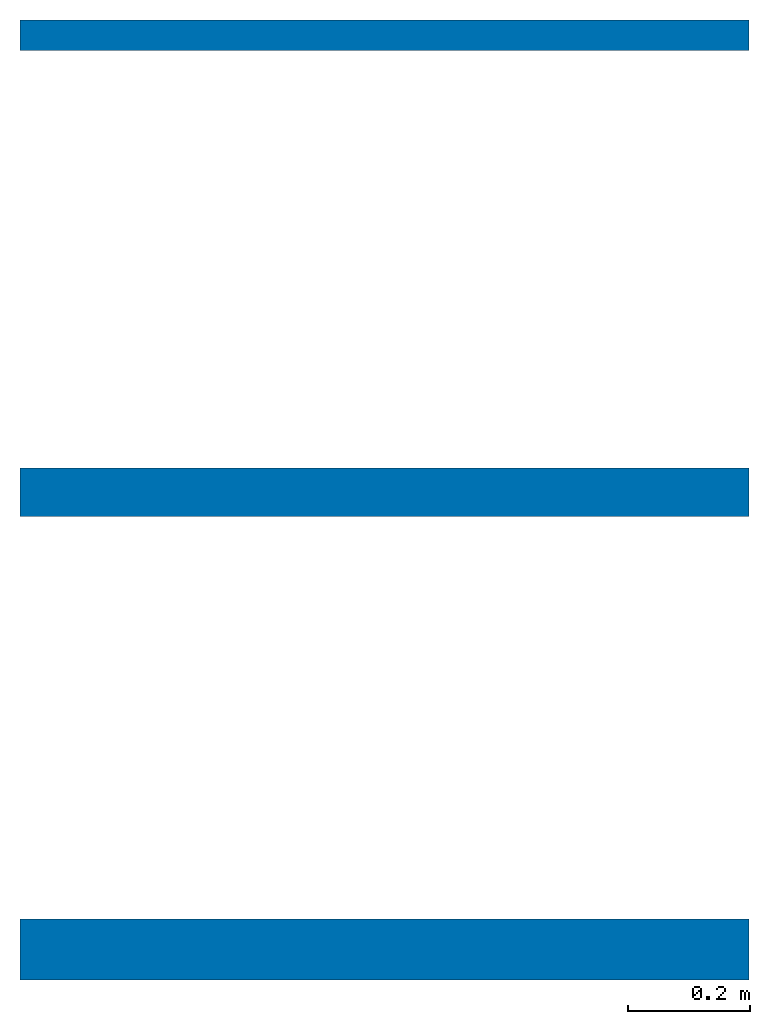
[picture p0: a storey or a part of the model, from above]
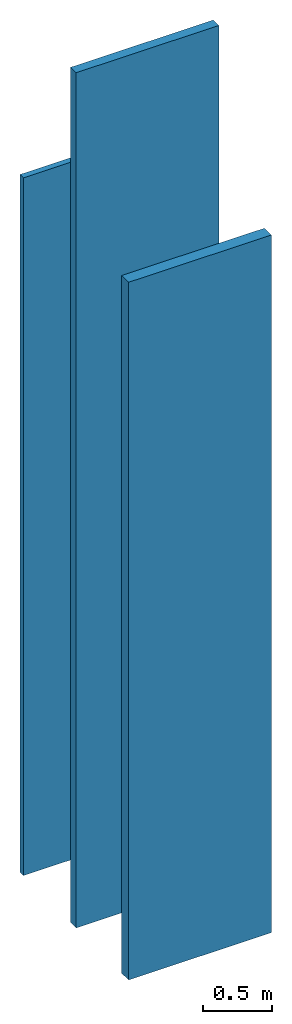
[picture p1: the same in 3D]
Properties of the parts of a building model (IFC2X3)

# File
Description: ViewDefinition [CoordinationView_V2.0]
File name: 0001
Time: 2018-02-28T12:59:43
Written by: The EXPRESS Data Manager Version 5.02.0100.07 : 28 Aug 2013
Made in: 20140606_1530(x64) - Exporter 15.6.0.0 - Alternate UI 15.6.0.0
Comment: STEP Physical File produced by: The EXPRESS Data Manager Version 5.02.0100.07 : 28 Aug 2013 * Module: EDMstepFileFactory/EDMstandAlone * Creation date: Wed Feb 28 12:59:43 2018 * Host: BRUTUS-02 * Database: C:\Users\MIGUEL~1\AppData\Local\Temp\{82EA2BB9-0C3D-4611-8605-79359C6E6EDA}\ifc * Database version: 5507 * Database creation date: Wed Feb 28 12:59:43 2018 * Schema: IFC2X3 * Model: DataRepository.ifc * Model creation date: Wed Feb 28 12:59:43 2018 * Header model: DataRepository.ifc_HeaderModel * Header model creation date: Wed Feb 28 12:59:43 2018 * EDMuser: sdai-user * EDMgroup: sdai-group * License ID and type: 5605 : Permanent license. Expiry date: * EDMstepFileFactory options: 020000

# IfcProject, 0001
LongName: Project Name; Phase: Project Status

# IfcSite, Default
RefLatitude: 42, 21, 30, 344238; RefLongitude: -71, -3, -35, -194702; RefElevation: 0 mm
Other - Category: Project Information; Client Name: Owner; Project Address: ## Street City, State Zip; Project Issue Date: Issue Date; Project Name: Project Name; Project Number: 0001; Project Status: Project Status

# IfcBuilding
Pset_BuildingCommon - NumberOfStoreys: 1
Other - Category: Project Information; Client Name: Owner; Project Address: ## Street City, State Zip; Project Issue Date: Issue Date; Project Name: Project Name; Project Number: 0001; Project Status: Project Status

# IfcBuildingStorey, Референтни ниво
LongName: Референтни ниво; Elevation: 0 mm
Other - Category: Levels; Family Name: Level; Family: Level: 8mm Head; Family and Type: Level: 8mm Head; Type: Level: 8mm Head; Type Id: Level: 8mm Head
Constraints - Elevation: 0 mm; Elevation Base: Project Base Point
Dimensions - Computation Height: 0 mm
Identity Data - Structural: no; Building Story: yes; Name: Референтни ниво; Type Name: 8mm Head
Graphics - Color: 0; Line Pattern: Center; Line Weight: 1; Symbol at End 1 Default: no; Symbol at End 2 Default: yes

# IfcWallStandardCase: Basic Wall:Knauf Insulation - NatuRoll Pro - 100 mm - 100 x 6200 x 1200 mm, Basic Wall:Knauf Insulation - NatuRoll Pro - 100 mm - 100 x 6200 x 1200 mm:208585
In: Референтни ниво
Type - PredefinedType: STANDARD; Material: Knauf Insulation - NatuRoll Pro - 100 mm - 100 x 6200 x 1200 mm 100 mm
Type - Analytical Properties - Roughness: 3; Absorptance: 0.7; Heat Transfer Coefficient (U): 0.39; Thermal mass: 887.5; Thermal Resistance (R): 2.5641
Type - Construction - Function: Exterior; Wrapping at Inserts: Do not wrap; Width: 100 mm
Type - Graphics - Coarse Scale Fill Color: 3951475
Type - Identity Data - Description: proizvod od staklene mineralne vune sa ECOSE® Technology. Pruža visoku zaštitu u pogledu termičke, zvučne i zaštite od požara.; KontaktE-mail: edin.dalifi@knaufinsulation.com; KontaktTelefon: +3811113310800; Manufacturer: Knauf Insulation; Model: NatuRoll Pro; No.: 88; Type Comments: namenjen je za primenu u unutrašnjim zidovima kao ispuna u suvomontažnim konstrukcijama sa gips-kartonskim pločama. Ukoliko se materijal upotrebljava u konstrukcijama sa različitim režimima grejanja, treba postaviti parnu branu sa toplije strane izolacionog materijala, ka strani koja je okrenuta grejanom prostoru, da bi se sprečilo prodiranje unutrašnje vlage u materijal. Koristi se i za izolaciju tavanskog prostora tako što se polaže na tavanicu. Ukoliko se materijal upotrebljava u konstrukcijama sa različitim režimima grejanja, treba postaviti parnu branu sa toplije strane izolacionog materijala, ka strani koja je okrenuta grejanom prostoru, da bi se sprečilo prodiranje unutrašnje vlage u materijal.; Type Name: Knauf Insulation - NatuRoll Pro - 100 mm - 100 x 6200 x 1200 mm
Type - Materials and Finishes - Structural Material: Knauf Insulation - NatuRoll Pro - 100 mm - 100 x 6200 x 1200 mm
Type - Other - Category: Walls; Family Name: Basic Wall
Constraints - Base Constraint: Level: Референтни ниво; Base Extension Distance: 0 mm; Base is Attached: no; Base Offset: 0 mm; Location Line: Wall Centerline; Related to Mass: no; Room Bounding: yes; Top Extension Distance: 0 mm; Top is Attached: no; Top Offset: 0 mm; Unconnected Height: 6200 mm
Dimensions - Area: 7.44 m2; Length: 1200 mm; Volume: 0.744 m3
Other - Family: Basic Wall: Knauf Insulation - NatuRoll Pro - 100 mm - 100 x 6200 x 1200 mm; Family and Type: Basic Wall: Knauf Insulation - NatuRoll Pro - 100 mm - 100 x 6200 x 1200 mm; Type: Basic Wall: Knauf Insulation - NatuRoll Pro - 100 mm - 100 x 6200 x 1200 mm; Type Id: Basic Wall: Knauf Insulation - NatuRoll Pro - 100 mm - 100 x 6200 x 1200 mm
Phasing - Phase Created: New Construction
Structural - Enable Analytical Model: no; Structural: no; Structural Usage: Non-bearing
Pset_WallCommon - LoadBearing: no; ExtendToStructure: no; IsExternal: yes; Reference: Knauf Insulation - NatuRoll Pro - 100 mm - 100 x 6200 x 1200 mm; ThermalTransmittance: 0.39 kg/K/s3
Pset_ManufacturerTypeInformation - Manufacturer: Knauf Insulation
Knauf Insulation Materijali - Zidovi - No.: 88

# IfcWallStandardCase: Basic Wall:Knauf Insulation - NatuRoll Pro - 50 mm -50 x 6200 x 1200 mm, Basic Wall:Knauf Insulation - NatuRoll Pro - 50 mm -50 x 6200 x 1200 mm:208091
In: Референтни ниво
Type - PredefinedType: STANDARD; Material: Knauf Insulation - NatuRoll Pro - 50 mm - 50 x 6200 x 1200 mm 50 mm
Type - Analytical Properties - Absorptance: 0.7; Heat Transfer Coefficient (U): 0.78; Roughness: 3; Thermal mass: 443.75; Thermal Resistance (R): 1.28205
Type - Construction - Function: Exterior; Width: 50 mm; Wrapping at Inserts: Do not wrap
Type - Graphics - Coarse Scale Fill Color: 3951475
Type - Identity Data - Description: proizvod od staklene mineralne vune sa ECOSE® Technology. Pruža visoku zaštitu u pogledu termičke, zvučne i zaštite od požara.; KontaktE-mail: edin.dalifi@knaufinsulation.com; KontaktTelefon: +3811113310800; Manufacturer: Knauf Insulation; Model: NatuRoll Pro; No.: 86; Type Comments: namenjen je za primenu u unutrašnjim zidovima kao ispuna u suvomontažnim konstrukcijama sa gips-kartonskim pločama. Ukoliko se materijal upotrebljava u konstrukcijama sa različitim režimima grejanja, treba postaviti parnu branu sa toplije strane izolacionog materijala, ka strani koja je okrenuta grejanom prostoru, da bi se sprečilo prodiranje unutrašnje vlage u materijal. Koristi se i za izolaciju tavanskog prostora tako što se polaže na tavanicu. Ukoliko se materijal upotrebljava u konstrukcijama sa različitim režimima grejanja, treba postaviti parnu branu sa toplije strane izolacionog materijala, ka strani koja je okrenuta grejanom prostoru, da bi se sprečilo prodiranje unutrašnje vlage u materijal.; Type Name: Knauf Insulation - NatuRoll Pro - 50 mm -50 x 6200 x 1200 mm
Type - Materials and Finishes - Structural Material: Knauf Insulation - NatuRoll Pro - 50 mm - 50 x 6200 x 1200 mm
Type - Other - Category: Walls; Family Name: Basic Wall
Constraints - Base Constraint: Level: Референтни ниво; Base Extension Distance: 0 mm; Base is Attached: no; Base Offset: 0 mm; Location Line: Wall Centerline; Related to Mass: no; Room Bounding: yes; Top Extension Distance: 0 mm; Top is Attached: no; Top Offset: 0 mm; Unconnected Height: 6200 mm
Dimensions - Area: 7.44 m2; Length: 1200 mm; Volume: 0.372 m3
Other - Family: Basic Wall: Knauf Insulation - NatuRoll Pro - 50 mm -50 x 6200 x 1200 mm; Family and Type: Basic Wall: Knauf Insulation - NatuRoll Pro - 50 mm -50 x 6200 x 1200 mm; Type: Basic Wall: Knauf Insulation - NatuRoll Pro - 50 mm -50 x 6200 x 1200 mm; Type Id: Basic Wall: Knauf Insulation - NatuRoll Pro - 50 mm -50 x 6200 x 1200 mm
Phasing - Phase Created: New Construction
Structural - Enable Analytical Model: no; Structural: no; Structural Usage: Non-bearing
Pset_WallCommon - Reference: Knauf Insulation - NatuRoll Pro - 50 mm -50 x 6200 x 1200 mm; LoadBearing: no; ExtendToStructure: no; IsExternal: yes; ThermalTransmittance: 0.78 kg/K/s3
Pset_ManufacturerTypeInformation - Manufacturer: Knauf Insulation
Knauf Insulation Materijali - Zidovi - No.: 86

# IfcWallStandardCase: Basic Wall:Knauf Insulation - NatuRoll Pro - 80 mm - 80 x 7600 x 1200 mm, Basic Wall:Knauf Insulation - NatuRoll Pro - 80 mm - 80 x 7600 x 1200 mm:208360
In: Референтни ниво
Type - PredefinedType: STANDARD; Material: Knauf Insulation - NatuRoll Pro - 80 mm - 80 x 7600 x 1200 mm 80 mm
Type - Analytical Properties - Roughness: 3; Absorptance: 0.7; Heat Transfer Coefficient (U): 0.4875; Thermal mass: 710; Thermal Resistance (R): 2.05128
Type - Construction - Function: Exterior; Wrapping at Inserts: Do not wrap; Width: 80 mm
Type - Graphics - Coarse Scale Fill Color: 3951475
Type - Identity Data - Description: proizvod od staklene mineralne vune sa ECOSE® Technology. Pruža visoku zaštitu u pogledu termičke, zvučne i zaštite od požara.; KontaktE-mail: edin.dalifi@knaufinsulation.com; KontaktTelefon: +3811113310800; Manufacturer: Knauf Insulation; Model: NatuRoll Pro; No.: 87; Type Comments: namenjen je za primenu u unutrašnjim zidovima kao ispuna u suvomontažnim konstrukcijama sa gips-kartonskim pločama. Ukoliko se materijal upotrebljava u konstrukcijama sa različitim režimima grejanja, treba postaviti parnu branu sa toplije strane izolacionog materijala, ka strani koja je okrenuta grejanom prostoru, da bi se sprečilo prodiranje unutrašnje vlage u materijal. Koristi se i za izolaciju tavanskog prostora tako što se polaže na tavanicu. Ukoliko se materijal upotrebljava u konstrukcijama sa različitim režimima grejanja, treba postaviti parnu branu sa toplije strane izolacionog materijala, ka strani koja je okrenuta grejanom prostoru, da bi se sprečilo prodiranje unutrašnje vlage u materijal.; Type Name: Knauf Insulation - NatuRoll Pro - 80 mm - 80 x 7600 x 1200 mm
Type - Materials and Finishes - Structural Material: Knauf Insulation - NatuRoll Pro - 80 mm - 80 x 7600 x 1200 mm
Type - Other - Category: Walls; Family Name: Basic Wall
Constraints - Base Constraint: Level: Референтни ниво; Base Extension Distance: 0 mm; Base is Attached: no; Base Offset: 0 mm; Location Line: Wall Centerline; Related to Mass: no; Room Bounding: yes; Top Extension Distance: 0 mm; Top is Attached: no; Top Offset: 0 mm; Unconnected Height: 7600 mm
Dimensions - Area: 9.12 m2; Length: 1200 mm; Volume: 0.7296 m3
Other - Family: Basic Wall: Knauf Insulation - NatuRoll Pro - 80 mm - 80 x 7600 x 1200 mm; Family and Type: Basic Wall: Knauf Insulation - NatuRoll Pro - 80 mm - 80 x 7600 x 1200 mm; Type: Basic Wall: Knauf Insulation - NatuRoll Pro - 80 mm - 80 x 7600 x 1200 mm; Type Id: Basic Wall: Knauf Insulation - NatuRoll Pro - 80 mm - 80 x 7600 x 1200 mm
Phasing - Phase Created: New Construction
Structural - Enable Analytical Model: no; Structural: no; Structural Usage: Non-bearing
Pset_WallCommon - LoadBearing: no; ExtendToStructure: no; IsExternal: yes; Reference: Knauf Insulation - NatuRoll Pro - 80 mm - 80 x 7600 x 1200 mm; ThermalTransmittance: 0.4875 kg/K/s3
Pset_ManufacturerTypeInformation - Manufacturer: Knauf Insulation
Knauf Insulation Materijali - Zidovi - No.: 87
